VERSION 5.7 ;
  NOWIREEXTENSIONATPIN ON ;
  DIVIDERCHAR "/" ;
  BUSBITCHARS "[]" ;
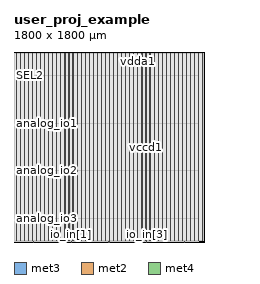
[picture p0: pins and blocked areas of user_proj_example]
MACRO user_proj_example
  CLASS BLOCK ;
  FOREIGN user_proj_example ;
  ORIGIN 0.000 0.000 ;
  SIZE 1800.000 BY 1800.000 ;
  PIN SEL2
    DIRECTION INOUT ;
    USE SIGNAL ;
    ANTENNADIFFAREA 0.434700 ;
    PORT
      LAYER met3 ;
        RECT 0.000 1574.920 4.000 1575.520 ;
    END
  END SEL2
  PIN analog_io1
    DIRECTION INPUT ;
    USE SIGNAL ;
    ANTENNAGATEAREA 0.495000 ;
    PORT
      LAYER met3 ;
        RECT 0.000 1124.760 4.000 1125.360 ;
    END
  END analog_io1
  PIN analog_io2
    DIRECTION INPUT ;
    USE SIGNAL ;
    ANTENNAGATEAREA 0.426000 ;
    PORT
      LAYER met3 ;
        RECT 0.000 674.600 4.000 675.200 ;
    END
  END analog_io2
  PIN analog_io3
    DIRECTION INPUT ;
    USE SIGNAL ;
    ANTENNAGATEAREA 0.426000 ;
    PORT
      LAYER met3 ;
        RECT 0.000 224.440 4.000 225.040 ;
    END
  END analog_io3
  PIN io_in[0]
    DIRECTION INPUT ;
    USE SIGNAL ;
    ANTENNAGATEAREA 0.159000 ;
    PORT
      LAYER met2 ;
        RECT 180.410 0.000 180.690 4.000 ;
    END
  END io_in[0]
  PIN io_in[1]
    DIRECTION INPUT ;
    USE SIGNAL ;
    ANTENNAGATEAREA 0.247500 ;
    PORT
      LAYER met2 ;
        RECT 540.130 0.000 540.410 4.000 ;
    END
  END io_in[1]
  PIN io_in[2]
    DIRECTION INPUT ;
    USE SIGNAL ;
    ANTENNAGATEAREA 0.247500 ;
    PORT
      LAYER met2 ;
        RECT 899.850 0.000 900.130 4.000 ;
    END
  END io_in[2]
  PIN io_in[3]
    DIRECTION INPUT ;
    USE SIGNAL ;
    ANTENNAGATEAREA 0.495000 ;
    PORT
      LAYER met2 ;
        RECT 1259.570 0.000 1259.850 4.000 ;
    END
  END io_in[3]
  PIN io_in[4]
    DIRECTION INPUT ;
    USE SIGNAL ;
    ANTENNAGATEAREA 0.852000 ;
    PORT
      LAYER met2 ;
        RECT 1619.290 0.000 1619.570 4.000 ;
    END
  END io_in[4]
  PIN vccd1
    DIRECTION INOUT ;
    USE POWER ;
    PORT
      LAYER met4 ;
        RECT 21.040 10.640 22.640 1787.280 ;
    END
    PORT
      LAYER met4 ;
        RECT 174.640 10.640 176.240 1787.280 ;
    END
    PORT
      LAYER met4 ;
        RECT 328.240 10.640 329.840 1787.280 ;
    END
    PORT
      LAYER met4 ;
        RECT 481.840 10.640 483.440 1787.280 ;
    END
    PORT
      LAYER met4 ;
        RECT 635.440 10.640 637.040 1787.280 ;
    END
    PORT
      LAYER met4 ;
        RECT 789.040 10.640 790.640 1787.280 ;
    END
    PORT
      LAYER met4 ;
        RECT 942.640 10.640 944.240 1787.280 ;
    END
    PORT
      LAYER met4 ;
        RECT 1096.240 10.640 1097.840 1787.280 ;
    END
    PORT
      LAYER met4 ;
        RECT 1249.840 10.640 1251.440 1787.280 ;
    END
    PORT
      LAYER met4 ;
        RECT 1403.440 10.640 1405.040 1787.280 ;
    END
    PORT
      LAYER met4 ;
        RECT 1557.040 10.640 1558.640 1787.280 ;
    END
    PORT
      LAYER met4 ;
        RECT 1710.640 10.640 1712.240 1787.280 ;
    END
  END vccd1
  PIN vdda1
    DIRECTION INOUT ;
    USE POWER ;
    PORT
      LAYER met4 ;
        RECT 97.840 10.640 99.440 1787.280 ;
    END
    PORT
      LAYER met4 ;
        RECT 251.440 10.640 253.040 1787.280 ;
    END
    PORT
      LAYER met4 ;
        RECT 405.040 10.640 406.640 1787.280 ;
    END
    PORT
      LAYER met4 ;
        RECT 558.640 10.640 560.240 1787.280 ;
    END
    PORT
      LAYER met4 ;
        RECT 712.240 10.640 713.840 1787.280 ;
    END
    PORT
      LAYER met4 ;
        RECT 865.840 10.640 867.440 1787.280 ;
    END
    PORT
      LAYER met4 ;
        RECT 1019.440 10.640 1021.040 1787.280 ;
    END
    PORT
      LAYER met4 ;
        RECT 1173.040 10.640 1174.640 1787.280 ;
    END
    PORT
      LAYER met4 ;
        RECT 1326.640 10.640 1328.240 1787.280 ;
    END
    PORT
      LAYER met4 ;
        RECT 1480.240 10.640 1481.840 1787.280 ;
    END
    PORT
      LAYER met4 ;
        RECT 1633.840 10.640 1635.440 1787.280 ;
    END
    PORT
      LAYER met4 ;
        RECT 1787.440 10.640 1789.040 1787.280 ;
    END
  END vdda1
  PIN vssa1
    DIRECTION INOUT ;
    USE GROUND ;
    PORT
      LAYER met4 ;
        RECT 136.240 10.640 137.840 1787.280 ;
    END
    PORT
      LAYER met4 ;
        RECT 289.840 10.640 291.440 1787.280 ;
    END
    PORT
      LAYER met4 ;
        RECT 443.440 10.640 445.040 1787.280 ;
    END
    PORT
      LAYER met4 ;
        RECT 597.040 10.640 598.640 1787.280 ;
    END
    PORT
      LAYER met4 ;
        RECT 750.640 10.640 752.240 1787.280 ;
    END
    PORT
      LAYER met4 ;
        RECT 904.240 10.640 905.840 1787.280 ;
    END
    PORT
      LAYER met4 ;
        RECT 1057.840 10.640 1059.440 1787.280 ;
    END
    PORT
      LAYER met4 ;
        RECT 1211.440 10.640 1213.040 1787.280 ;
    END
    PORT
      LAYER met4 ;
        RECT 1365.040 10.640 1366.640 1787.280 ;
    END
    PORT
      LAYER met4 ;
        RECT 1518.640 10.640 1520.240 1787.280 ;
    END
    PORT
      LAYER met4 ;
        RECT 1672.240 10.640 1673.840 1787.280 ;
    END
  END vssa1
  PIN vssd1
    DIRECTION INOUT ;
    USE GROUND ;
    PORT
      LAYER met4 ;
        RECT 59.440 10.640 61.040 1787.280 ;
    END
    PORT
      LAYER met4 ;
        RECT 213.040 10.640 214.640 1787.280 ;
    END
    PORT
      LAYER met4 ;
        RECT 366.640 10.640 368.240 1787.280 ;
    END
    PORT
      LAYER met4 ;
        RECT 520.240 10.640 521.840 1787.280 ;
    END
    PORT
      LAYER met4 ;
        RECT 673.840 10.640 675.440 1787.280 ;
    END
    PORT
      LAYER met4 ;
        RECT 827.440 10.640 829.040 1787.280 ;
    END
    PORT
      LAYER met4 ;
        RECT 981.040 10.640 982.640 1787.280 ;
    END
    PORT
      LAYER met4 ;
        RECT 1134.640 10.640 1136.240 1787.280 ;
    END
    PORT
      LAYER met4 ;
        RECT 1288.240 10.640 1289.840 1787.280 ;
    END
    PORT
      LAYER met4 ;
        RECT 1441.840 10.640 1443.440 1787.280 ;
    END
    PORT
      LAYER met4 ;
        RECT 1595.440 10.640 1597.040 1787.280 ;
    END
    PORT
      LAYER met4 ;
        RECT 1749.040 10.640 1750.640 1787.280 ;
    END
  END vssd1
  OBS
      LAYER li1 ;
        RECT 5.520 10.795 1794.460 1787.125 ;
      LAYER met1 ;
        RECT 4.670 10.640 1794.460 1787.280 ;
      LAYER met2 ;
        RECT 4.690 4.280 1750.610 1787.225 ;
        RECT 4.690 4.000 180.130 4.280 ;
        RECT 180.970 4.000 539.850 4.280 ;
        RECT 540.690 4.000 899.570 4.280 ;
        RECT 900.410 4.000 1259.290 4.280 ;
        RECT 1260.130 4.000 1619.010 4.280 ;
        RECT 1619.850 4.000 1750.610 4.280 ;
      LAYER met3 ;
        RECT 4.000 1575.920 1750.630 1787.205 ;
        RECT 4.400 1574.520 1750.630 1575.920 ;
        RECT 4.000 1125.760 1750.630 1574.520 ;
        RECT 4.400 1124.360 1750.630 1125.760 ;
        RECT 4.000 675.600 1750.630 1124.360 ;
        RECT 4.400 674.200 1750.630 675.600 ;
        RECT 4.000 225.440 1750.630 674.200 ;
        RECT 4.400 224.040 1750.630 225.440 ;
        RECT 4.000 10.715 1750.630 224.040 ;
      LAYER met4 ;
        RECT 528.375 11.735 530.545 634.945 ;
  END
END user_proj_example
END LIBRARY

